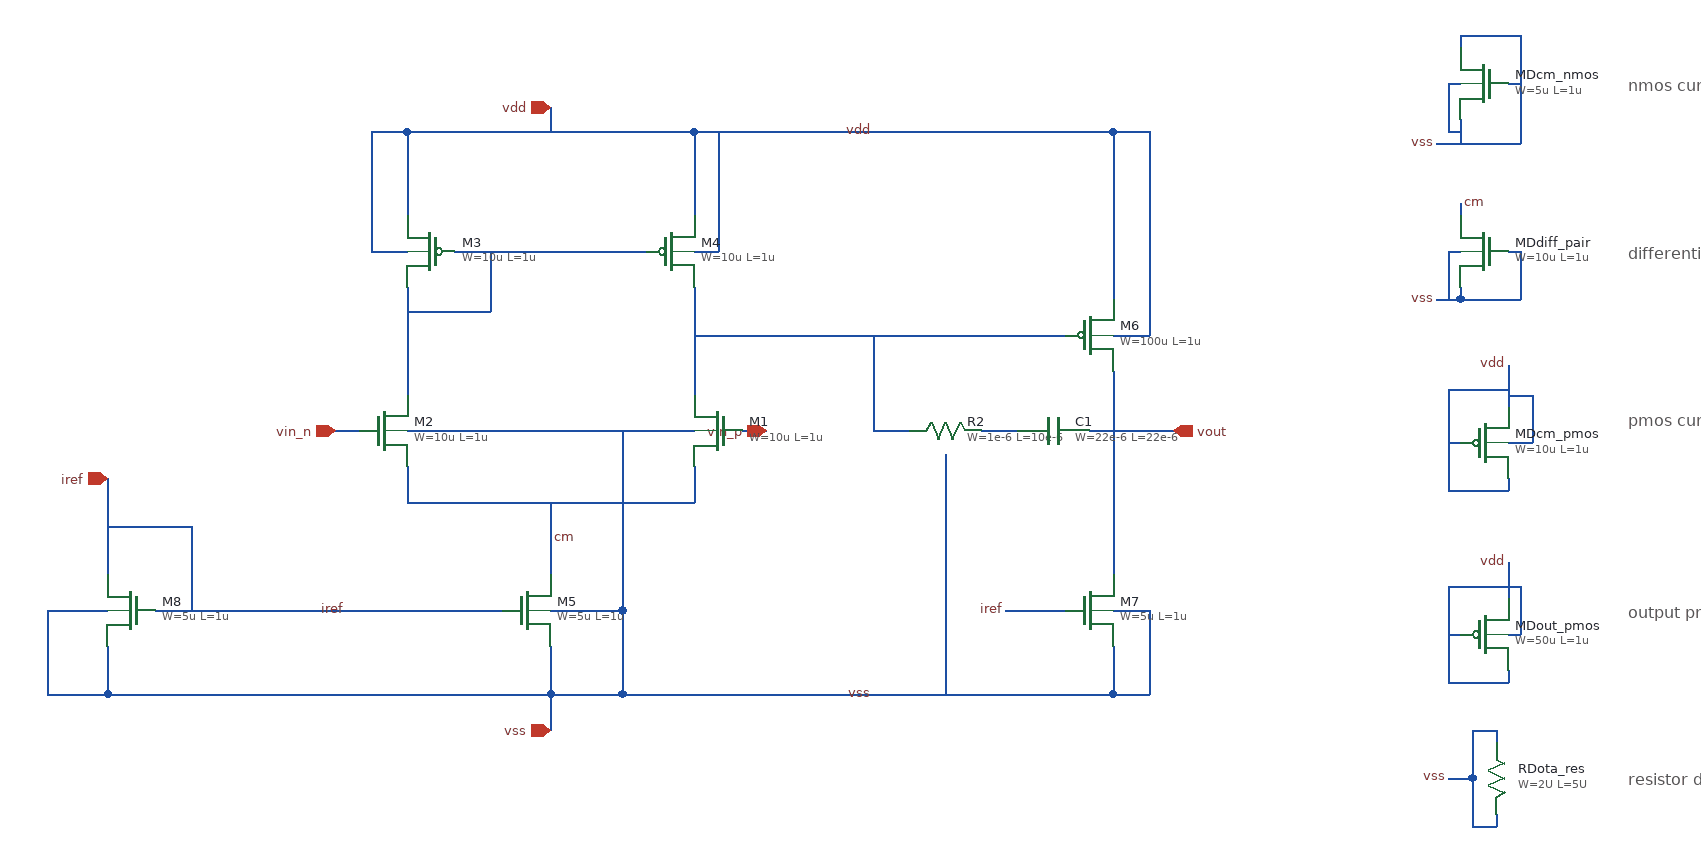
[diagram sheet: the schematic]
v {xschem version=3.4.5 file_version=1.2
}
G {}
K {}
V {}
S {}
E {}
T {nmos current mirror dummy} 900 -300 0 0 0.4 0.4 {}
T {differential pair dummy} 900 -160 0 0 0.4 0.4 {}
T {pmos current mirror dummy} 900 -20 0 0 0.4 0.4 {}
T {output pmos dummy} 900 140 0 0 0.4 0.4 {}
T {resistor dummy} 900 280 0 0 0.4 0.4 {}
N 120 30 120 60 {
lab=cm}
N -120 60 120 60 {
lab=cm}
N -120 30 -120 60 {
lab=cm}
N 0 60 0 120 {
lab=cm}
N -370 180 -370 220 {
lab=vss}
N -370 220 -0 220 {
lab=vss}
N -0 180 -0 220 {
lab=vss}
N -330 150 -40 150 {
lab=iref}
N -370 40 -370 120 {
lab=iref}
N -300 100 -300 150 {
lab=iref}
N -300 80 -300 100 {
lab=iref}
N -370 80 -300 80 {
lab=iref}
N -420 150 -370 150 {
lab=vss}
N -420 150 -420 220 {
lab=vss}
N -420 220 -370 220 {
lab=vss}
N 0 150 60 150 {
lab=vss}
N 60 150 60 220 {
lab=vss}
N 0 220 60 220 {
lab=vss}
N -80 -150 20 -150 {
lab=#net1}
N -120 -120 -120 -30 {
lab=#net1}
N -120 -250 60 -250 {
lab=vdd}
N -120 -250 -120 -180 {
lab=vdd}
N -120 -0 120 0 {
lab=vss}
N 20 -150 80 -150 {
lab=#net1}
N 120 -250 120 -180 {
lab=vdd}
N 60 -250 120 -250 {
lab=vdd}
N 120 -120 120 -30 {
lab=#net2}
N 120 -80 370 -80 {
lab=#net2}
N 470 -250 470 -110 {
lab=vdd}
N 120 -250 410 -250 {
lab=vdd}
N 470 -50 470 120 {
lab=vout}
N 470 180 470 220 {
lab=vss}
N 60 220 410 220 {
lab=vss}
N 420 150 430 150 {
lab=iref}
N 380 150 420 150 {
lab=iref}
N 370 -80 430 -80 {
lab=#net2}
N 410 220 470 220 {
lab=vss}
N 410 -250 470 -250 {
lab=vdd}
N 360 0 390 0 {
lab=#net3}
N 270 0 300 0 {
lab=#net2}
N 450 0 470 0 {
lab=vout}
N 270 -80 270 -0 {
lab=#net2}
N -180 0 -160 -0 {
lab=vin_n}
N 160 0 180 0 {
lab=vin_p}
N -150 -150 -120 -150 {
lab=vdd}
N -150 -250 -150 -150 {
lab=vdd}
N -150 -250 -120 -250 {
lab=vdd}
N 120 -150 140 -150 {
lab=vdd}
N 140 -250 140 -150 {
lab=vdd}
N 470 -80 500 -80 {
lab=vdd}
N 500 -250 500 -80 {
lab=vdd}
N 470 -250 500 -250 {
lab=vdd}
N 470 150 480 150 {
lab=vss}
N 480 150 500 150 {
lab=vss}
N 500 150 500 220 {
lab=vss}
N 470 220 500 220 {
lab=vss}
N -0 -270 0 -250 {
lab=vdd}
N -0 220 -0 250 {
lab=vss}
N 470 0 520 -0 {
lab=vout}
N -50 -150 -50 -100 {
lab=#net1}
N -120 -100 -50 -100 {
lab=#net1}
N 60 -0 60 150 {
lab=vss}
N 330 20 330 220 {
lab=vss}
N 760 -330 760 -320 {
lab=vss}
N 760 -330 810 -330 {
lab=vss}
N 810 -330 810 -240 {
lab=vss}
N 800 -290 810 -290 {
lab=vss}
N 760 -260 760 -240 {
lab=vss}
N 750 -290 760 -290 {
lab=vss}
N 750 -290 750 -250 {
lab=vss}
N 750 -250 760 -250 {
lab=vss}
N 740 -240 810 -240 {
lab=vss}
N 800 10 820 10 {
lab=vdd}
N 800 -55 800 -20 {
lab=vdd}
N 800 -35 800 -20 {
lab=vdd}
N 750 -35 800 -35 {
lab=vdd}
N 750 -35 750 50 {
lab=vdd}
N 750 50 800 50 {
lab=vdd}
N 800 40 800 50 {
lab=vdd}
N 750 10 760 10 {
lab=vdd}
N 820 -30 820 10 {
lab=vdd}
N 800 -30 820 -30 {
lab=vdd}
N 760 -190 760 -180 {
lab=cm}
N 760 -110 810 -110 {
lab=vss}
N 760 -120 760 -110 {
lab=vss}
N 800 -150 810 -150 {
lab=vss}
N 770 330 790 330 {
lab=vss}
N 770 290 770 330 {
lab=vss}
N 750 290 770 290 {
lab=vss}
N 790 250 790 260 {
lab=vss}
N 770 250 790 250 {
lab=vss}
N 770 250 770 290 {
lab=vss}
N 790 320 790 330 {
lab=vss}
N 800 110 800 140 {
lab=vdd}
N 750 130 800 130 {
lab=vdd}
N 750 130 750 210 {
lab=vdd}
N 750 210 800 210 {
lab=vdd}
N 800 200 800 210 {
lab=vdd}
N 750 170 760 170 {
lab=vdd}
N 800 170 810 170 {
lab=vdd}
N 810 130 810 170 {
lab=vdd}
N 800 130 810 130 {
lab=vdd}
N 810 -150 810 -110 {
lab=vss}
N 750 -150 760 -150 {
lab=vss}
N 750 -150 750 -110 {
lab=vss}
N 740 -110 760 -110 {
lab=vss}
C {symbols/nfet_03v3.sym} -140 0 0 0 {name=M2
L=1u
W=10u
nf=1
m=1
ad="'int((nf+1)/2) * W/nf * 0.18u'"
pd="'2*int((nf+1)/2) * (W/nf + 0.18u)'"
as="'int((nf+2)/2) * W/nf * 0.18u'"
ps="'2*int((nf+2)/2) * (W/nf + 0.18u)'"
nrd="'0.18u / W'" nrs="'0.18u / W'"
sa=0 sb=0 sd=0
model=nfet_03v3
spiceprefix=X
}
C {symbols/nfet_03v3.sym} -20 150 0 0 {name=M5
L=1u
W=5u
nf=1
m=1
ad="'int((nf+1)/2) * W/nf * 0.18u'"
pd="'2*int((nf+1)/2) * (W/nf + 0.18u)'"
as="'int((nf+2)/2) * W/nf * 0.18u'"
ps="'2*int((nf+2)/2) * (W/nf + 0.18u)'"
nrd="'0.18u / W'" nrs="'0.18u / W'"
sa=0 sb=0 sd=0
model=nfet_03v3
spiceprefix=X
}
C {symbols/nfet_03v3.sym} -350 150 0 1 {name=M8
L=1u
W=5u
nf=1
m=1
ad="'int((nf+1)/2) * W/nf * 0.18u'"
pd="'2*int((nf+1)/2) * (W/nf + 0.18u)'"
as="'int((nf+2)/2) * W/nf * 0.18u'"
ps="'2*int((nf+2)/2) * (W/nf + 0.18u)'"
nrd="'0.18u / W'" nrs="'0.18u / W'"
sa=0 sb=0 sd=0
model=nfet_03v3
spiceprefix=X
}
C {symbols/nfet_03v3.sym} 450 150 0 0 {name=M7
L=1u
W=5u
nf=1
m=5
ad="'int((nf+1)/2) * W/nf * 0.18u'"
pd="'2*int((nf+1)/2) * (W/nf + 0.18u)'"
as="'int((nf+2)/2) * W/nf * 0.18u'"
ps="'2*int((nf+2)/2) * (W/nf + 0.18u)'"
nrd="'0.18u / W'" nrs="'0.18u / W'"
sa=0 sb=0 sd=0
model=nfet_03v3
spiceprefix=X
}
C {devices/lab_pin.sym} 380 150 0 0 {name=p1 sig_type=std_logic lab=iref}
C {devices/lab_pin.sym} -170 150 0 0 {name=p2 sig_type=std_logic lab=iref}
C {devices/ipin.sym} -370 40 1 0 {name=p3 lab=iref}
C {devices/ipin.sym} -180 0 0 0 {name=p4 lab=vin_n}
C {devices/ipin.sym} 180 0 2 0 {name=p5 lab=vin_p}
C {devices/iopin.sym} 0 -270 3 0 {name=p6 lab=vdd}
C {devices/iopin.sym} 0 250 1 0 {name=p7 lab=vss}
C {devices/opin.sym} 520 0 0 0 {name=p8 lab=vout}
C {devices/lab_pin.sym} 270 -250 0 0 {name=p9 sig_type=std_logic lab=vdd}
C {devices/lab_pin.sym} 270 220 0 0 {name=p11 sig_type=std_logic lab=vss}
C {symbols/nfet_03v3.sym} 140 0 0 1 {name=M1
L=1u
W=10u
nf=1
m=1
ad="'int((nf+1)/2) * W/nf * 0.18u'"
pd="'2*int((nf+1)/2) * (W/nf + 0.18u)'"
as="'int((nf+2)/2) * W/nf * 0.18u'"
ps="'2*int((nf+2)/2) * (W/nf + 0.18u)'"
nrd="'0.18u / W'" nrs="'0.18u / W'"
sa=0 sb=0 sd=0
model=nfet_03v3
spiceprefix=X
}
C {symbols/pfet_03v3.sym} -100 -150 0 1 {name=M3
L=1u
W=10u
nf=1
m=1
ad="'int((nf+1)/2) * W/nf * 0.18u'"
pd="'2*int((nf+1)/2) * (W/nf + 0.18u)'"
as="'int((nf+2)/2) * W/nf * 0.18u'"
ps="'2*int((nf+2)/2) * (W/nf + 0.18u)'"
nrd="'0.18u / W'" nrs="'0.18u / W'"
sa=0 sb=0 sd=0
model=pfet_03v3
spiceprefix=X
}
C {symbols/pfet_03v3.sym} 450 -80 0 0 {name=M6
L=1u
W=100u
nf=1
m=1
ad="'int((nf+1)/2) * W/nf * 0.18u'"
pd="'2*int((nf+1)/2) * (W/nf + 0.18u)'"
as="'int((nf+2)/2) * W/nf * 0.18u'"
ps="'2*int((nf+2)/2) * (W/nf + 0.18u)'"
nrd="'0.18u / W'" nrs="'0.18u / W'"
sa=0 sb=0 sd=0
model=pfet_03v3
spiceprefix=X
}
C {symbols/pfet_03v3.sym} 100 -150 0 0 {name=M4
L=1u
W=10u
nf=1
m=1
ad="'int((nf+1)/2) * W/nf * 0.18u'"
pd="'2*int((nf+1)/2) * (W/nf + 0.18u)'"
as="'int((nf+2)/2) * W/nf * 0.18u'"
ps="'2*int((nf+2)/2) * (W/nf + 0.18u)'"
nrd="'0.18u / W'" nrs="'0.18u / W'"
sa=0 sb=0 sd=0
model=pfet_03v3
spiceprefix=X
}
C {symbols/ppolyf_u.sym} 330 0 3 0 {name=R2
W=1e-6
L=10e-6
model=ppolyf_u_1k
spiceprefix=X
m=1}
C {symbols/cap_mim_2f0fF.sym} 420 0 1 0 {name=C1
W=22e-6
L=22e-6
model=cap_mim_2f0_m4m5_noshield
spiceprefix=X
m=1}
C {symbols/nfet_03v3.sym} 780 -290 0 1 {name=MDcm_nmos
L=1u
W=5u
nf=1
m=5
ad="'int((nf+1)/2) * W/nf * 0.18u'"
pd="'2*int((nf+1)/2) * (W/nf + 0.18u)'"
as="'int((nf+2)/2) * W/nf * 0.18u'"
ps="'2*int((nf+2)/2) * (W/nf + 0.18u)'"
nrd="'0.18u / W'" nrs="'0.18u / W'"
sa=0 sb=0 sd=0
model=nfet_03v3
spiceprefix=X
}
C {devices/lab_pin.sym} 740 -240 0 0 {name=p10 sig_type=std_logic lab=vss}
C {symbols/pfet_03v3.sym} 780 10 0 0 {name=MDcm_pmos
L=1u
W=10u
nf=1
m=1
ad="'int((nf+1)/2) * W/nf * 0.18u'"
pd="'2*int((nf+1)/2) * (W/nf + 0.18u)'"
as="'int((nf+2)/2) * W/nf * 0.18u'"
ps="'2*int((nf+2)/2) * (W/nf + 0.18u)'"
nrd="'0.18u / W'" nrs="'0.18u / W'"
sa=0 sb=0 sd=0
model=pfet_03v3
spiceprefix=X
}
C {devices/lab_pin.sym} 800 -55 0 0 {name=p12 sig_type=std_logic lab=vdd}
C {symbols/nfet_03v3.sym} 780 -150 0 1 {name=MDdiff_pair
L=1u
W=10u
nf=1
m=1
ad="'int((nf+1)/2) * W/nf * 0.18u'"
pd="'2*int((nf+1)/2) * (W/nf + 0.18u)'"
as="'int((nf+2)/2) * W/nf * 0.18u'"
ps="'2*int((nf+2)/2) * (W/nf + 0.18u)'"
nrd="'0.18u / W'" nrs="'0.18u / W'"
sa=0 sb=0 sd=0
model=nfet_03v3
spiceprefix=X
}
C {devices/lab_pin.sym} 760 -190 2 0 {name=p13 sig_type=std_logic lab=cm}
C {devices/lab_pin.sym} 740 -110 0 0 {name=p14 sig_type=std_logic lab=vss}
C {devices/lab_pin.sym} 0 90 2 0 {name=p15 sig_type=std_logic lab=cm}
C {symbols/ppolyf_u.sym} 790 290 0 0 {name=RDota_res
W=2U
L=5U
model=ppolyf_u_1k
spiceprefix=X
m=1}
C {devices/lab_pin.sym} 750 290 0 0 {name=p16 sig_type=std_logic lab=vss}
C {symbols/pfet_03v3.sym} 780 170 0 0 {name=MDout_pmos
L=1u
W=50u
nf=1
m=1
ad="'int((nf+1)/2) * W/nf * 0.18u'"
pd="'2*int((nf+1)/2) * (W/nf + 0.18u)'"
as="'int((nf+2)/2) * W/nf * 0.18u'"
ps="'2*int((nf+2)/2) * (W/nf + 0.18u)'"
nrd="'0.18u / W'" nrs="'0.18u / W'"
sa=0 sb=0 sd=0
model=pfet_03v3
spiceprefix=X
}
C {devices/lab_pin.sym} 800 110 0 0 {name=p17 sig_type=std_logic lab=vdd}
